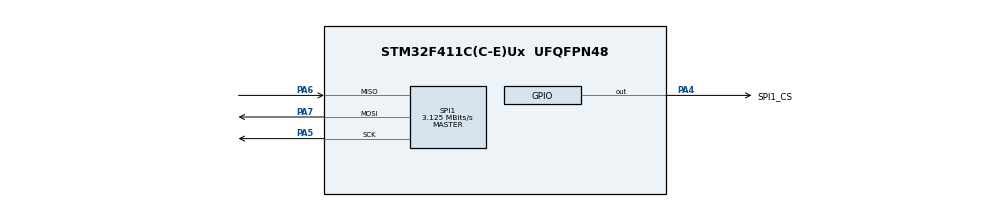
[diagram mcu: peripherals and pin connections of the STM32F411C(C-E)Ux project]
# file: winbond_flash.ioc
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Mcu.Family=STM32F4
Mcu.Name=STM32F411C(C-E)Ux
Mcu.Package=UFQFPN48
NVIC.PriorityGroup=NVIC_PRIORITYGROUP_4
PA13.Mode=Serial_Wire
PA13.Signal=SYS_JTMS-SWDIO
PA14.Mode=Serial_Wire
PA14.Signal=SYS_JTCK-SWCLK
PA4.GPIO_Label=SPI1_CS
PA4.GPIO_PuPd=GPIO_NOPULL
PA4.GPIO_Speed=GPIO_SPEED_FREQ_VERY_HIGH
PA4.PinState=GPIO_PIN_SET
PA4.Signal=GPIO_Output
PA5.Mode=Full_Duplex_Master
PA5.Signal=SPI1_SCK
PA6.Mode=Full_Duplex_Master
PA6.Signal=SPI1_MISO
PA7.Mode=Full_Duplex_Master
PA7.Signal=SPI1_MOSI
PH0\ -\ OSC_IN.Mode=HSE-External-Oscillator
PH0\ -\ OSC_IN.Signal=RCC_OSC_IN
PH1\ -\ OSC_OUT.Mode=HSE-External-Oscillator
PH1\ -\ OSC_OUT.Signal=RCC_OSC_OUT
ProjectManager.HeapSize=0x200
ProjectManager.StackSize=0x400
ProjectManager.TargetToolchain=CMake
RCC.48MHZClocksFreq_Value=50000000
RCC.AHBFreq_Value=100000000
RCC.APB1CLKDivider=RCC_HCLK_DIV2
RCC.APB1Freq_Value=50000000
RCC.APB1TimFreq_Value=100000000
RCC.APB2Freq_Value=100000000
RCC.APB2TimFreq_Value=100000000
RCC.CortexFreq_Value=100000000
RCC.HCLKFreq_Value=100000000
RCC.HSE_VALUE=25000000
RCC.HSI_VALUE=16000000
RCC.LSE_VALUE=32768
RCC.PLLM=12
RCC.PLLN=96
RCC.PLLSourceVirtual=RCC_PLLSOURCE_HSE
RCC.SYSCLKFreq_VALUE=100000000
RCC.SYSCLKSource=RCC_SYSCLKSOURCE_PLLCLK
RCC.VCOOutputFreq_Value=200000000
SPI1.BaudRatePrescaler=SPI_BAUDRATEPRESCALER_32
SPI1.CalculateBaudRate=3.125 MBits/s
SPI1.Direction=SPI_DIRECTION_2LINES
SPI1.Mode=SPI_MODE_MASTER
SPI1.VirtualType=VM_MASTER
board=custom

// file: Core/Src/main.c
/* USER CODE BEGIN Header */
/**
  ******************************************************************************
  * @file           : main.c
  * @brief          : Main program body
  ******************************************************************************
  * @attention
  *
  * Copyright (c) 2025 STMicroelectronics.
  * All rights reserved.
  *
  * This software is licensed under terms that can be found in the LICENSE file
  * in the root directory of this software component.
  * If no LICENSE file comes with this software, it is provided AS-IS.
  *
  ******************************************************************************
  */
/* USER CODE END Header */
#include "main.h"

/* USER CODE BEGIN Includes */
#include "w25q128.h"
/* USER CODE END Includes */

SPI_HandleTypeDef hspi1;

void SystemClock_Config(void);
static void MX_GPIO_Init(void);
static void MX_SPI1_Init(void);

int main(void)
{

  /* USER CODE BEGIN 1 */
  uint32_t ID = 0;
  uint8_t receive_buffer1[64] = {0};
  uint8_t receive_buffer2[256] = {0};

  W25Q128_TypeDef w25;
  w25.cs_port = GPIOA;
  w25.cs_pin = GPIO_PIN_4;
  w25.hspi = &hspi1;

  /* USER CODE END 1 */

  /* MCU Configuration--------------------------------------------------------*/

  /* Reset of all peripherals, Initializes the Flash interface and the Systick. */
  HAL_Init();

  /* Configure the system clock */
  SystemClock_Config();

  /* Initialize all configured peripherals */
  MX_GPIO_Init();
  MX_SPI1_Init();

  /* Infinite loop */
  /* USER CODE BEGIN WHILE */
  uint8_t tx_data[] = "abcdefgh123456789!";

  W25Q128_Reset(&w25);
  ID = W25Q128_ReadID(&w25, ID_JEDEC);

  W25Q128_Read(&w25, 0, 0, 30, receive_buffer1);

  W25Q128_EraseSector(&w25, 0);

  W25Q128_Read(&w25, 0, 0, 30, receive_buffer1);

  W25Q128_WritePage(&w25, 0, 0, sizeof(tx_data), tx_data);

  W25Q128_Read(&w25, 0, 0, 30, receive_buffer1);

  while (1)
  {
    /* USER CODE END WHILE */

  }
}

void SystemClock_Config(void)
{
  RCC_OscInitTypeDef RCC_OscInitStruct = {0};
  RCC_ClkInitTypeDef RCC_ClkInitStruct = {0};

  /** Configure the main internal regulator output voltage
  */
  __HAL_RCC_PWR_CLK_ENABLE();
  __HAL_PWR_VOLTAGESCALING_CONFIG(PWR_REGULATOR_VOLTAGE_SCALE1);

  /** Initializes the RCC Oscillators according to the specified parameters
  * in the RCC_OscInitTypeDef structure.
  */
  RCC_OscInitStruct.OscillatorType = RCC_OSCILLATORTYPE_HSE;
  RCC_OscInitStruct.HSEState = RCC_HSE_ON;
  RCC_OscInitStruct.PLL.PLLState = RCC_PLL_ON;
  RCC_OscInitStruct.PLL.PLLSource = RCC_PLLSOURCE_HSE;
  RCC_OscInitStruct.PLL.PLLM = 12;
  RCC_OscInitStruct.PLL.PLLN = 72;
  RCC_OscInitStruct.PLL.PLLP = RCC_PLLP_DIV6;
  RCC_OscInitStruct.PLL.PLLQ = 4;
  if (HAL_RCC_OscConfig(&RCC_OscInitStruct) != HAL_OK)
  {
    Error_Handler();
  }

  /** Initializes the CPU, AHB and APB buses clocks
  */
  RCC_ClkInitStruct.ClockType = RCC_CLOCKTYPE_HCLK|RCC_CLOCKTYPE_SYSCLK
                              |RCC_CLOCKTYPE_PCLK1|RCC_CLOCKTYPE_PCLK2;
  RCC_ClkInitStruct.SYSCLKSource = RCC_SYSCLKSOURCE_PLLCLK;
  RCC_ClkInitStruct.AHBCLKDivider = RCC_SYSCLK_DIV1;
  RCC_ClkInitStruct.APB1CLKDivider = RCC_HCLK_DIV2;
  RCC_ClkInitStruct.APB2CLKDivider = RCC_HCLK_DIV1;

  if (HAL_RCC_ClockConfig(&RCC_ClkInitStruct, FLASH_LATENCY_0) != HAL_OK)
  {
    Error_Handler();
  }
}

static void MX_SPI1_Init(void)
{

  /* SPI1 parameter configuration*/
  hspi1.Instance = SPI1;
  hspi1.Init.Mode = SPI_MODE_MASTER;
  hspi1.Init.Direction = SPI_DIRECTION_2LINES;
  hspi1.Init.DataSize = SPI_DATASIZE_8BIT;
  hspi1.Init.CLKPolarity = SPI_POLARITY_HIGH;
  hspi1.Init.CLKPhase = SPI_PHASE_2EDGE;
  hspi1.Init.NSS = SPI_NSS_SOFT;
  hspi1.Init.BaudRatePrescaler = SPI_BAUDRATEPRESCALER_16;
  hspi1.Init.FirstBit = SPI_FIRSTBIT_MSB;
  hspi1.Init.TIMode = SPI_TIMODE_DISABLE;
  hspi1.Init.CRCCalculation = SPI_CRCCALCULATION_DISABLE;
  hspi1.Init.CRCPolynomial = 10;
  if (HAL_SPI_Init(&hspi1) != HAL_OK)
  {
    Error_Handler();
  }

}

static void MX_GPIO_Init(void)
{
  GPIO_InitTypeDef GPIO_InitStruct = {0};

  /* GPIO Ports Clock Enable */
  __HAL_RCC_GPIOH_CLK_ENABLE();
  __HAL_RCC_GPIOA_CLK_ENABLE();

  /*Configure GPIO pin Output Level */
  HAL_GPIO_WritePin(SPI1_CS_GPIO_Port, SPI1_CS_Pin, GPIO_PIN_SET);

  /*Configure GPIO pin : SPI1_CS_Pin */
  GPIO_InitStruct.Pin = SPI1_CS_Pin;
  GPIO_InitStruct.Mode = GPIO_MODE_OUTPUT_PP;
  GPIO_InitStruct.Pull = GPIO_NOPULL;
  GPIO_InitStruct.Speed = GPIO_SPEED_FREQ_VERY_HIGH;
  HAL_GPIO_Init(SPI1_CS_GPIO_Port, &GPIO_InitStruct);

}

void Error_Handler(void)
{
  __disable_irq();
  while (1)
  {
  }
}
